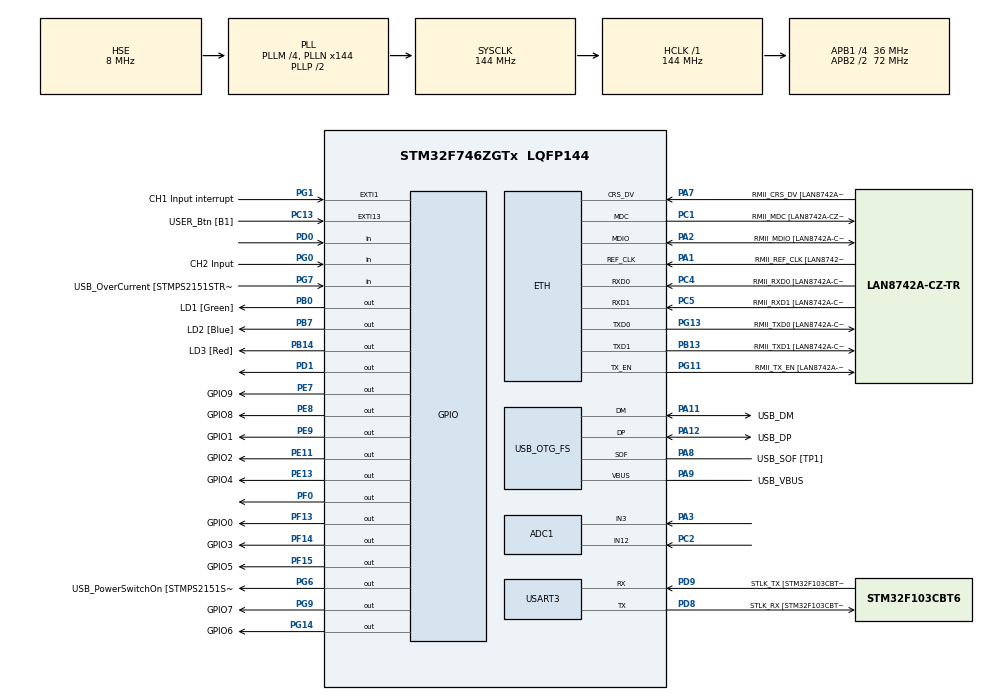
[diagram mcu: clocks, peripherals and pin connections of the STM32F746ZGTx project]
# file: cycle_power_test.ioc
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ADC1.Channel-0\#ChannelRegularConversion=ADC_CHANNEL_12
ADC1.NbrOfConversion=1
ADC1.NbrOfConversionFlag=1
ADC1.Rank-0\#ChannelRegularConversion=1
ADC1.SamplingTime-0\#ChannelRegularConversion=ADC_SAMPLETIME_3CYCLES
ADC1.master=1
ETH.MediaInterface=ETH_MEDIA_INTERFACE_RMII
ETH.PHY_Name=LAN8742A_PHY_ADDRESS
ETH.PHY_Value=0
ETH.PhyAddress=0
Mcu.Family=STM32F7
Mcu.Name=STM32F746ZGTx
Mcu.Package=LQFP144
NVIC.EXTI1_IRQn=true\:0\:0\:false\:false\:true\:true\:true\:true
NVIC.PriorityGroup=NVIC_PRIORITYGROUP_4
NVIC.TIM8_TRG_COM_TIM14_IRQn=true\:0\:0\:false\:false\:true\:true\:true\:true
PA1.GPIO_Label=RMII_REF_CLK [LAN8742A-CZ-TR_REFCLK0]
PA1.Mode=RMII
PA1.Signal=ETH_REF_CLK
PA10.GPIO_Label=USB_ID
PA10.Signal=USB_OTG_FS_ID
PA11.GPIO_Label=USB_DM
PA11.Mode=Device_Only
PA11.Signal=USB_OTG_FS_DM
PA12.GPIO_Label=USB_DP
PA12.Mode=Device_Only
PA12.Signal=USB_OTG_FS_DP
PA13.GPIO_Label=TMS
PA13.Mode=Serial_Wire
PA13.Signal=SYS_JTMS-SWDIO
PA14.GPIO_Label=TCK
PA14.Mode=Serial_Wire
PA14.Signal=SYS_JTCK-SWCLK
PA2.GPIO_Label=RMII_MDIO [LAN8742A-CZ-TR_MDIO]
PA2.Mode=RMII
PA2.Signal=ETH_MDIO
PA3.Signal=ADCx_IN3
PA7.GPIO_Label=RMII_CRS_DV [LAN8742A-CZ-TR_CRS_DV]
PA7.Mode=RMII
PA7.Signal=ETH_CRS_DV
PA8.GPIO_Label=USB_SOF [TP1]
PA8.Mode=Activate_SOF_FS
PA8.Signal=USB_OTG_FS_SOF
PA9.GPIO_Label=USB_VBUS
PA9.Mode=Activate_VBUS
PA9.Signal=USB_OTG_FS_VBUS
PB0.GPIO_Label=LD1 [Green]
PB0.PinState=GPIO_PIN_RESET
PB0.Signal=GPIO_Output
PB13.GPIO_Label=RMII_TXD1 [LAN8742A-CZ-TR_TXD1]
PB13.Mode=RMII
PB13.Signal=ETH_TXD1
PB14.GPIO_Label=LD3 [Red]
PB14.Signal=GPIO_Output
PB3.GPIO_Label=SW0
PB3.Signal=SYS_JTDO-SWO
PB7.GPIO_Label=LD2 [Blue]
PB7.Signal=GPIO_Output
PC1.GPIO_Label=RMII_MDC [LAN8742A-CZ-TR_MDC]
PC1.Mode=RMII
PC1.Signal=ETH_MDC
PC13.GPIO_Label=USER_Btn [B1]
PC13.Signal=GPXTI13
PC14/OSC32_IN.Mode=LSE-External-Oscillator
PC14/OSC32_IN.Signal=RCC_OSC32_IN
PC15/OSC32_OUT.Mode=LSE-External-Oscillator
PC15/OSC32_OUT.Signal=RCC_OSC32_OUT
PC2.Signal=ADCx_IN12
PC4.GPIO_Label=RMII_RXD0 [LAN8742A-CZ-TR_RXD0]
PC4.Mode=RMII
PC4.Signal=ETH_RXD0
PC5.GPIO_Label=RMII_RXD1 [LAN8742A-CZ-TR_RXD1]
PC5.Mode=RMII
PC5.Signal=ETH_RXD1
PD0.Signal=GPIO_Input
PD1.PinState=GPIO_PIN_RESET
PD1.Signal=GPIO_Output
PD8.GPIO_Label=STLK_RX [STM32F103CBT6_PA3]
PD8.Mode=Asynchronous
PD8.Signal=USART3_TX
PD9.GPIO_Label=STLK_TX [STM32F103CBT6_PA2]
PD9.Mode=Asynchronous
PD9.Signal=USART3_RX
PE11.GPIO_Label=GPIO2
PE11.PinState=GPIO_PIN_RESET
PE11.Signal=GPIO_Output
PE13.GPIO_Label=GPIO4
PE13.PinState=GPIO_PIN_RESET
PE13.Signal=GPIO_Output
PE7.GPIO_Label=GPIO9
PE7.PinState=GPIO_PIN_RESET
PE7.Signal=GPIO_Output
PE8.GPIO_Label=GPIO8
PE8.PinState=GPIO_PIN_RESET
PE8.Signal=GPIO_Output
PE9.GPIO_Label=GPIO1
PE9.PinState=GPIO_PIN_RESET
PE9.Signal=GPIO_Output
PF0.Signal=GPIO_Output
PF13.GPIO_Label=GPIO0
PF13.PinState=GPIO_PIN_RESET
PF13.Signal=GPIO_Output
PF14.GPIO_Label=GPIO3
PF14.PinState=GPIO_PIN_RESET
PF14.Signal=GPIO_Output
PF15.GPIO_Label=GPIO5
PF15.PinState=GPIO_PIN_RESET
PF15.Signal=GPIO_Output
PG0.GPIO_Label=CH2 Input
PG0.Signal=GPIO_Input
PG1.GPIO_Label=CH1 Input interrupt
PG1.GPIO_ModeDefaultEXTI=GPIO_MODE_IT_RISING_FALLING
PG1.Signal=GPXTI1
PG11.GPIO_Label=RMII_TX_EN [LAN8742A-CZ-TR_TXEN]
PG11.Mode=RMII
PG11.Signal=ETH_TX_EN
PG13.GPIO_Label=RMII_TXD0 [LAN8742A-CZ-TR_TXD0]
PG13.Mode=RMII
PG13.Signal=ETH_TXD0
PG14.GPIO_Label=GPIO6
PG14.PinState=GPIO_PIN_RESET
PG14.Signal=GPIO_Output
PG6.GPIO_Label=USB_PowerSwitchOn [STMPS2151STR_EN]
PG6.Signal=GPIO_Output
PG7.GPIO_Label=USB_OverCurrent [STMPS2151STR_FAULT]
PG7.Signal=GPIO_Input
PG9.GPIO_Label=GPIO7
PG9.PinState=GPIO_PIN_RESET
PG9.Signal=GPIO_Output
PH0/OSC_IN.GPIO_Label=MCO [STM32F103CBT6_PA8]
PH0/OSC_IN.Mode=HSE-External-Clock-Source
PH0/OSC_IN.Signal=RCC_OSC_IN
PH1/OSC_OUT.Mode=HSE-External-Clock-Source
PH1/OSC_OUT.Signal=RCC_OSC_OUT
ProjectManager.HeapSize=0x200
ProjectManager.StackSize=0x400
ProjectManager.TargetToolchain=STM32CubeIDE
RCC.48MHZClocksFreq_Value=24000000
RCC.AHBFreq_Value=144000000
RCC.APB1CLKDivider=RCC_HCLK_DIV4
RCC.APB1Freq_Value=36000000
RCC.APB1TimFreq_Value=72000000
RCC.APB2CLKDivider=RCC_HCLK_DIV2
RCC.APB2Freq_Value=72000000
RCC.APB2TimFreq_Value=144000000
RCC.CortexFreq_Value=144000000
RCC.HCLKFreq_Value=144000000
RCC.HSE_VALUE=8000000
RCC.HSI_VALUE=16000000
RCC.PLLM=4
RCC.PLLMUL=RCC_PLL_MUL9
RCC.PLLN=144
RCC.PLLQ=6
RCC.PRESCALERUSB=RCC_USBCLKSOURCE_PLL_DIV1_5
RCC.SYSCLKFreq_VALUE=144000000
RCC.SYSCLKSource=RCC_SYSCLKSOURCE_PLLCLK
RCC.SYSCLKSourceVirtual=RCC_SYSCLKSOURCE_PLLCLK
RCC.USBFreq_Value=48000000
RCC.VCOOutputFreq_Value=288000000
SH.ADCx_IN12.0=ADC1_IN12,IN12
SH.ADCx_IN3.0=ADC1_IN3,IN3
TIM14.Period=10000
TIM14.Prescaler=7200 -1 
USART3.VirtualMode-Asynchronous=VM_ASYNC
USB_OTG_FS.VirtualMode=Device_Only
VP_TIM14_VS_ClockSourceINT.Mode=Enable_Timer
board=NUCLEO-F746ZG

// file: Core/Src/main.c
/* USER CODE BEGIN Header */
/**
  ******************************************************************************
  * @file           : main.c
  * @brief          : Main program body
  ******************************************************************************
  * @attention
  *
  * Copyright (c) 2022 STMicroelectronics.
  * All rights reserved.
  *
  * This software is licensed under terms that can be found in the LICENSE file
  * in the root directory of this software component.
  * If no LICENSE file comes with this software, it is provided AS-IS.
  * Code written for AMTEC.PRO by Primož Peitl
  *
  ******************************************************************************
  */
/* USER CODE END Header */
#include "main.h"

/* USER CODE BEGIN Includes */
#include "string.h"
#include "stdio.h"
/* USER CODE END Includes */

/* USER CODE BEGIN PD */
#define DO_NOCURRENT_TEST 0
#define NO_CURRENT_ADC_VAL			1600
#define CURRENT_PRESENT_ADC_VAL		1700
#define ENABLE_IDLE_NTC_TOGGLE		0

//output pins
#define RUNNING				GPIO_PIN_0		//GPIOF
#define NTC_BANK			GPIO_PIN_8		//GPIOF
#define GEN_NO_ERROR		GPIO_PIN_7		//GPIOF
#define GEN_WARNING			GPIO_PIN_2		//GPIOD
#define CH2_TRIGGER			GPIO_PIN_9		//GPIOF
#define DEBUG_OFF_OUTPUT	0

//input pins

//Errors
#define LOW_CURRENT_ERROR	1

/* USER CODE END PD */

ADC_HandleTypeDef hadc1;

ETH_HandleTypeDef heth;

TIM_HandleTypeDef htim14;

UART_HandleTypeDef huart3;

PCD_HandleTypeDef hpcd_USB_OTG_FS;

/* USER CODE BEGIN PV */
volatile int activeCount 	= 0;

int i;
int cntDly 					= 0;
int my_HAL_Delay 			= 1;
float voltageSense;
int shuntValues[11];
int StartSet 				= 0;
int CurrADC_Val				= 0;
int cntNr [11];
int CycleNr 				= 0;
int NrOfADCs 				= 0;
int currVals[2000];
int curValsCntr 			= 0;
int currValsMax, currValsMin;
long  	IdleCounter 		= 0;
long  	OnStartDelay 		= 0;
volatile int 	CH2PulsCounter		= 0;
uint32_t CH1PulsCounter		= 0;
uint32_t CH1NegCounter		= 0;
volatile uint32_t intCH1PulsCounter	= 0;
volatile uint32_t intCH1NegCounter 	= 0;
volatile int32_t intDetected 		= 0;
volatile uint32_t startCNT;
uint32_t startNTCtoggle	= 0;
GPIO_PinState prev_CH1;
GPIO_PinState prev_CH2;
GPIO_PinState current_CH1;
GPIO_PinState current_CH2;
GPIO_PinState current_sense;
GPIO_PinState StartProcess;
GPIO_PinState GPTestEnabled;
GPIO_PinState RstBlockValues;

GPIO_PinState PLCClk;
GPIO_PinState PLCResData;
GPIO_PinState prev_PLCClock;
GPIO_PinState prev_PLCResData;
GPIO_PinState prev_StartProcess;

GPIO_PinState PLCClk_GP		= 0;
GPIO_PinState PLCResData_GP	= 0;
GPIO_PinState prev_PLCClock_GP;
GPIO_PinState prev_PLCResData_GP;

uint32_t ADC_currentPresent_val;
uint32_t ADC_noCurrent_val;

int PLCClockCounter_val;
uint16_t PLC_ClockIdleTicks = 0;
uint16_t ValuesPLCResData 	= 0x3ff;

int PLCClockCounterGP_val;
uint16_t GP_Cycles_tmp 		= 0;
uint16_t GP_Cycles			= 0;
uint32_t PLC_ClockIdleTicks_GP;

int FalseLowCurrentCounter;
int ErrorNr = 0;

unsigned int isPG0low 		= 0;
char myString[50];
char msg[255];
unsigned int FalsePG1;
unsigned int NrOfChanges_PG1;
unsigned char TestRunning;
unsigned int Counter1, Counter2,Counter3;

/* USER CODE END PV */

void SystemClock_Config(void);
static void MX_GPIO_Init(void);
static void MX_ETH_Init(void);
static void MX_USART3_UART_Init(void);
static void MX_USB_OTG_FS_PCD_Init(void);
static void MX_TIM14_Init(void);
static void MX_ADC1_Init(void);

/* USER CODE BEGIN PFP */
void ToggleNTCBank();
int CheckIdleCurrent();
void IdleCurrentMeasurementTest();
void DWT_Init(void);
/* USER CODE END PFP */

/* USER CODE BEGIN 0 */

// ----------------------------------------------------------------------------
// communication between PLC and MPU
// which parts are good and which are not
// ----------------------------------------------------------------------------
void BadPartDetect() {
uint16_t tmpVal;
	PLCClk		= HAL_GPIO_ReadPin(GPIOF, GPIO_PIN_1);			//PLC Clock
	PLCResData	= HAL_GPIO_ReadPin(GPIOE, GPIO_PIN_3);			//PLC resistor data

	if (PLCClockCounter_val > 9) PLCClockCounter_val = 0;

	//detect clock rise signal
	if (prev_PLCClock == GPIO_PIN_RESET && PLCClk == GPIO_PIN_SET)
	{
		if (PLCResData == GPIO_PIN_RESET) {
			tmpVal = (1 << PLCClockCounter_val);
			tmpVal = ~tmpVal;
			ValuesPLCResData &= tmpVal;
		}
		PLCClockCounter_val++;
	}

	// longer PLCClk reset means reset for PLCClockCounter_val
	if (PLCClk == GPIO_PIN_RESET) PLC_ClockIdleTicks++;
	else PLC_ClockIdleTicks = 0;

	if (PLC_ClockIdleTicks >= 10000) {
		/*
		if ((PLC_ClockIdleTicks == 10000) && (ValuesPLCResData != 0x3FF)) {
			sprintf(msg, "PLCClockCounter_val: %d, ValuesPLCResData:%d \r\n ",PLCClockCounter_val,ValuesPLCResData);
			HAL_UART_Transmit(&huart3, (uint8_t*)msg, strlen(msg), HAL_MAX_DELAY);
		}
		*/
		PLC_ClockIdleTicks = 10001;
		PLCClockCounter_val = 0;
	}

	prev_PLCClock = PLCClk;
	prev_PLCResData = PLCResData;
}

void GPTest_NrOfCycles() {
	PLCClk_GP		= HAL_GPIO_ReadPin(GPIOF, GPIO_PIN_1);				//PLC Clock
	PLCResData_GP	= HAL_GPIO_ReadPin(GPIOE, GPIO_PIN_3);				//PLC resistor data
	if (PLCClockCounterGP_val > 9) PLCClockCounterGP_val = 0;
	//detect clock rise signal
	if (prev_PLCClock_GP == GPIO_PIN_RESET && PLCClk_GP == GPIO_PIN_SET)
	{
		//GP_Cycles_tmp = GP_Cycles_tmp + 2^PLCClockCounterGP_val;
		if (PLCResData_GP == GPIO_PIN_SET) {
			GP_Cycles_tmp = GP_Cycles_tmp + (uint16_t)(1 << PLCClockCounterGP_val);
			//GP_Cycles_tmp += 1;
			//uint16_t GP_Cycles = 0;
		}
		PLCClockCounterGP_val++;
	}

	// longer PLCClk reset means reset for PLCClockCounter_val
	if (PLCClk_GP == GPIO_PIN_RESET) PLC_ClockIdleTicks_GP++;
	else PLC_ClockIdleTicks_GP = 0;

	if (PLC_ClockIdleTicks_GP >= 10000) {
		if (PLC_ClockIdleTicks_GP == 10000){
			GP_Cycles = GP_Cycles_tmp;
			GP_Cycles_tmp = 0;
			sprintf(msg, "GP_Cycles: %d\r\n ",GP_Cycles);
			HAL_UART_Transmit(&huart3, (uint8_t*)msg, strlen(msg), HAL_MAX_DELAY);
		}
		PLC_ClockIdleTicks_GP = 10001;
		PLCClockCounterGP_val = 0;
	}

	prev_PLCClock_GP = PLCClk_GP;
	prev_PLCResData_GP = PLCResData_GP;
}

// ----------------------------------------------------------------------------
// ADC read task
// ----------------------------------------------------------------------------
void ADCReadTask(){
	//start ADC conversion every 20 cycles
	if (cntDly % 20 == 0) {
		HAL_ADC_Start(&hadc1);

		HAL_StatusTypeDef myADC_Status 								= HAL_ADC_PollForConversion(&hadc1 , 100);
		if 		(myADC_Status == HAL_OK )			CurrADC_Val 	+= HAL_ADC_GetValue(&hadc1);
		else if (myADC_Status == HAL_TIMEOUT) 		CurrADC_Val 	= 9999;
		else 										CurrADC_Val 	= 9998;

		NrOfADCs++;
		shuntValues[activeCount] = CurrADC_Val / NrOfADCs;
		HAL_ADC_Stop(&hadc1);
	}
	cntNr[activeCount] = cntDly;
	cntDly++;
	return;
}

void ReadADC() {
	if (prev_CH1 == GPIO_PIN_RESET) {
		cntDly 			= 0;
		CurrADC_Val 	= 0;
		NrOfADCs 		= 0;
	}
	ADCReadTask();
	return;
}

void ReadADC_Low() {
	if (prev_CH1 == GPIO_PIN_SET) {
		cntDly 			= 0;
		CurrADC_Val 	= 0;
		NrOfADCs 		= 0;
	}
	ADCReadTask();
	return;
}

uint32_t ReadADC_cont() {
uint32_t myADC_val;

	//start ADC conversion
	HAL_ADC_Start(&hadc1);
	HAL_StatusTypeDef myADC_Status = HAL_ADC_PollForConversion(&hadc1 , 100);
	if 		(myADC_Status == HAL_OK )			myADC_val = HAL_ADC_GetValue(&hadc1);
	else if (myADC_Status == HAL_TIMEOUT) 		myADC_val = 9999;
	else 										myADC_val = 9998;

	myADC_val = HAL_ADC_GetValue(&hadc1);

	HAL_ADC_Stop(&hadc1);
	if (curValsCntr >= 0 && curValsCntr < 2000) {
		currVals[curValsCntr] = myADC_val;
		curValsCntr++;
	}
	return myADC_val;
}

/* USER CODE END 0 */

int main(void)
{

	/* MCU Configuration--------------------------------------------------------*/

	/* Reset of all peripherals, Initialises the Flash interface and the Systick. */
	HAL_Init();

	/* Configure the system clock */
	SystemClock_Config();

	/* Initialise all configured peripherals */
	MX_GPIO_Init();
	if (0) MX_ETH_Init();				// disabled
	MX_USART3_UART_Init();
	if (0) MX_USB_OTG_FS_PCD_Init();  // disabled
	if (0) MX_TIM14_Init();			// disabled
	MX_ADC1_Init();

	/* USER CODE BEGIN 2 */
	DWT_Init();
	/* USER CODE END 2 */

	/* USER CODE BEGIN WHILE */
	HAL_GPIO_WritePin(GPIOB, LD2_Pin, GPIO_PIN_RESET);
	sprintf(msg, "BOOTING \r\n");
	HAL_UART_Transmit(&huart3, (uint8_t*)msg, strlen(msg), HAL_MAX_DELAY);

	ADC_currentPresent_val 	= CURRENT_PRESENT_ADC_VAL;		// store constant values to variables
	ADC_noCurrent_val 		= NO_CURRENT_ADC_VAL;
	StartSet = 1;												// low start state must be detected before
															// before doing first start
	HAL_GPIO_WritePin(GPIOF, CH2_TRIGGER, GPIO_PIN_RESET);	// reset trigger for CH2

  /* USER CODE END WHILE */

  /* USER CODE BEGIN 3 */
	HAL_GPIO_WritePin(GPIOF, GPIO_PIN_13, 	GPIO_PIN_RESET);
	HAL_GPIO_WritePin(GPIOE, GPIO_PIN_9, 	GPIO_PIN_RESET);
	HAL_GPIO_WritePin(GPIOE, GPIO_PIN_11, 	GPIO_PIN_RESET);
	HAL_GPIO_WritePin(GPIOF, GPIO_PIN_14, 	GPIO_PIN_RESET);
	HAL_GPIO_WritePin(GPIOE, GPIO_PIN_13, 	GPIO_PIN_RESET);
	HAL_GPIO_WritePin(GPIOF, GPIO_PIN_15, 	GPIO_PIN_RESET);
	HAL_GPIO_WritePin(GPIOG, GPIO_PIN_14, 	GPIO_PIN_RESET);
	HAL_GPIO_WritePin(GPIOG, GPIO_PIN_9, 	GPIO_PIN_RESET);
	HAL_GPIO_WritePin(GPIOE, GPIO_PIN_8, 	GPIO_PIN_RESET);
	HAL_GPIO_WritePin(GPIOE, GPIO_PIN_7, 	GPIO_PIN_RESET);
	activeCount = 0;		//select first IGBT. It will switch on after start signal
/* Infinite loop */
	startNTCtoggle	= HAL_GetTick();
	while (1) {
//detect input signals
		current_CH1 	= HAL_GPIO_ReadPin(GPIOG, GPIO_PIN_1);			//CH1 from generator
		current_CH2 	= HAL_GPIO_ReadPin(GPIOG, GPIO_PIN_0);			//CH2 from generator
		StartProcess 	= HAL_GPIO_ReadPin(GPIOF, GPIO_PIN_2);			//Start pulse from PLC
		GPTestEnabled	= HAL_GPIO_ReadPin(GPIOE, GPIO_PIN_6);			//GP signal from PLC
		RstBlockValues	= HAL_GPIO_ReadPin(GPIOE, GPIO_PIN_1);			//Start pulse from PLC

//detect start pulse from PLC
		if (OnStartDelay++ > 20000) OnStartDelay = 20000;
		if (StartProcess == GPIO_PIN_SET && StartSet == 0 && OnStartDelay > 10000)
		{
			HAL_GPIO_WritePin(GPIOF, CH2_TRIGGER, GPIO_PIN_SET);	//trigger ch2
			StartSet 		= 1;
			ErrorNr 		= 0;											//reset errors when start pulse
			Counter1++;
		}
		else if (StartProcess == GPIO_PIN_RESET && StartSet == 1)
		{
			HAL_GPIO_WritePin(GPIOF, CH2_TRIGGER, GPIO_PIN_RESET);	//reset trigger for CH2
			StartSet = 0;
			Counter2++;
		}
// this happens only at the start of the cycle
// if cyclecount > 1 this doesn't occurs
		if  (StartProcess == GPIO_PIN_RESET && GPTestEnabled == GPIO_PIN_SET)
		{
			ValuesPLCResData 	= 0x3ff;
			intCH1PulsCounter 	= 0;
			intCH1NegCounter 	= 0;
			CH2PulsCounter 		= 0;
			HAL_GPIO_WritePin(GPIOF, NTC_BANK, GPIO_PIN_RESET);		//reset temperature bank select pin
			startNTCtoggle	= HAL_GetTick();
		}
//switch on warrning light
		if (prev_CH2 == GPIO_PIN_RESET && current_CH2 == GPIO_PIN_SET) {
			HAL_GPIO_WritePin(GPIOD, GEN_WARNING, GPIO_PIN_SET);
		}
//RstBlockValues reset command
		if (RstBlockValues)
		{
			sprintf(msg, "RstBlockValues ON\r\n");
			HAL_UART_Transmit(&huart3, (uint8_t*)msg, strlen(msg), HAL_MAX_DELAY);
			ValuesPLCResData 	= 0x3ff;
			intCH1PulsCounter 	= 0;
			CH2PulsCounter 		= 0;
		}
		if (Counter1 > 65000) Counter1=0;
		if (Counter2 > 65000) Counter2=0;

//detect not allowed input signals
		if (current_CH1 == GPIO_PIN_SET && (current_CH2 == GPIO_PIN_RESET || StartProcess == GPIO_PIN_RESET)) FalsePG1++;
		if (prev_CH1 != current_CH1) NrOfChanges_PG1++;

// toggle NTC bank
		if ((HAL_GetTick() - startNTCtoggle >= 500) && (StartProcess == GPIO_PIN_SET))
		{
			startNTCtoggle += 500;
			HAL_GPIO_TogglePin(GPIOF, NTC_BANK);
			//sprintf(msg, "0x%X \r\n",ValuesPLCResData);
			//HAL_UART_Transmit(&huart3, (uint8_t*)msg, strlen(msg), HAL_MAX_DELAY);
		}

		if(current_CH2 == GPIO_PIN_SET && StartProcess == GPIO_PIN_SET && ErrorNr == 0 && OnStartDelay > 10000) {
			//this is done in interrupt
		}
		else {
	// switch off outputs
	// interrupt hasen't occurred for a intDetected cycles
			intDetected--;
			int32_t t_initDetect = intDetected;
			if (t_initDetect == 0) {
				__disable_irq();
				HAL_GPIO_WritePin(GPIOF, GPIO_PIN_13, 	GPIO_PIN_RESET);
				HAL_GPIO_WritePin(GPIOE, GPIO_PIN_9, 	GPIO_PIN_RESET);
				HAL_GPIO_WritePin(GPIOE, GPIO_PIN_11, 	GPIO_PIN_RESET);
				HAL_GPIO_WritePin(GPIOF, GPIO_PIN_14, 	GPIO_PIN_RESET);
				HAL_GPIO_WritePin(GPIOE, GPIO_PIN_13, 	GPIO_PIN_RESET);
				HAL_GPIO_WritePin(GPIOF, GPIO_PIN_15, 	GPIO_PIN_RESET);
				HAL_GPIO_WritePin(GPIOG, GPIO_PIN_14, 	GPIO_PIN_RESET);
				HAL_GPIO_WritePin(GPIOG, GPIO_PIN_9, 	GPIO_PIN_RESET);
				HAL_GPIO_WritePin(GPIOE, GPIO_PIN_8, 	GPIO_PIN_RESET);
				HAL_GPIO_WritePin(GPIOE, GPIO_PIN_7, 	GPIO_PIN_RESET);
				activeCount = 0; 											//select first IGBT. It will switch on after start signal
				__enable_irq();
				uint32_t end = DWT->CYCCNT;
				uint32_t cycles = end - startCNT;
				uint32_t us = cycles / (SystemCoreClock / 1000000U);
				sprintf(msg, "Reset IGBTs: %1u\r\n", (uint16_t)us);
				HAL_UART_Transmit(&huart3, (uint8_t*)msg, strlen(msg), HAL_MAX_DELAY);
			}
			else if (t_initDetect < 0) {
				intDetected = -1;
			//reset output RUNNING
				IdleCounter++;

				if (IdleCounter == 42000) {
					uint32_t end = DWT->CYCCNT;
					uint32_t cycles = end - startCNT;
					uint32_t us = cycles / (SystemCoreClock / 1000000U);
					HAL_GPIO_WritePin(GPIOF, RUNNING,	GPIO_PIN_RESET);
					sprintf(msg, "Reset RUNNING: %1u\r\n", us);
					HAL_UART_Transmit(&huart3, (uint8_t*)msg, strlen(msg), HAL_MAX_DELAY);
				}
				if (IdleCounter > 100000) IdleCounter = 100000;

		//toggle NTC bank in idle state - if enabled
				if (ENABLE_IDLE_NTC_TOGGLE) ToggleNTCBank();

				//write low level values - test
				if (DO_NOCURRENT_TEST) IdleCurrentMeasurementTest();
			}
		}
	 // call bad part detection procedure
		if (!GPTestEnabled)
		{
			BadPartDetect();
		}
		// check for GP test nr of cycles
		if (StartProcess == GPIO_PIN_RESET && GPTestEnabled ) {
			GPTest_NrOfCycles();
		}

		if (StartProcess == GPIO_PIN_RESET && StartProcess !=prev_StartProcess) {
			sprintf(msg, "Measurement finished: %u, %u, 0x%x\r\n", CH1PulsCounter, CH1NegCounter, ValuesPLCResData);
			HAL_UART_Transmit(&huart3, (uint8_t*)msg, strlen(msg), HAL_MAX_DELAY);
		}

		// remember state of inputs
		 prev_CH1 = current_CH1;
		 prev_CH2 = current_CH2;
		 prev_StartProcess = StartProcess;
		 CH1PulsCounter = intCH1PulsCounter;
		 CH1NegCounter 	= intCH1NegCounter;
	}
  /* USER CODE END 3 */
}

void HAL_GPIO_EXTI_Callback( uint16_t GPIO_Pin)	//Interrupt for GPIO pins
{
	char tmpResult;
	GPIO_PinState	EXTI_current_CH1 	= HAL_GPIO_ReadPin(GPIOG, GPIO_PIN_1);			//CH1 from generator
	GPIO_PinState 	EXTI_current_CH2 	= HAL_GPIO_ReadPin(GPIOG, GPIO_PIN_0);			//CH2 from generator
	GPIO_PinState 	EXTI_StartProcess 	= HAL_GPIO_ReadPin(GPIOF, GPIO_PIN_2);			//Start pulse from PLC

	//if (EXTI_current_CH1 == GPIO_PIN_SET) intCH1PulsCounter++;
	intDetected = 40000;
	startCNT = DWT->CYCCNT;

//	if(GPIO_Pin == GPIO_PIN_1 && EXTI_current_CH1 == GPIO_PIN_SET && EXTI_current_CH2 == GPIO_PIN_SET && EXTI_StartProcess == GPIO_PIN_SET && ErrorNr == 0 && OnStartDelay > 10000) {
	if(GPIO_Pin == GPIO_PIN_1 && EXTI_current_CH1 == GPIO_PIN_SET && EXTI_StartProcess == GPIO_PIN_SET && ErrorNr == 0 && OnStartDelay > 10000) {
		 HAL_GPIO_WritePin(GPIOF, RUNNING,	GPIO_PIN_SET);
		 IdleCounter = 0;
		 curValsCntr = 0;
		 intCH1PulsCounter++;
	 //***************************************************
	 //************* Forcing all IGBTs to work
	 //***************************************************
		 if (intCH1PulsCounter == 1) ValuesPLCResData = 0x3ff;
	 //***************************************************
	 //***************************************************
	 //***************************************************
		 switch (activeCount) {
			case 0:
			//	HAL_GPIO_WritePin(GPIOF, GPIO_PIN_13,	GPIO_PIN_SET && (CH2PulsCounter != 50) && !(GPTestEnabled && CH2PulsCounter > 50) && (ValuesPLCResData & (1 << activeCount)));
				tmpResult = !(GPTestEnabled && CH2PulsCounter > 50) && (ValuesPLCResData & (1 << activeCount));
				HAL_GPIO_WritePin(GPIOF, GPIO_PIN_13,	GPIO_PIN_SET && tmpResult);
				HAL_GPIO_WritePin(GPIOE, GPIO_PIN_9, 	GPIO_PIN_RESET);
				HAL_GPIO_WritePin(GPIOE, GPIO_PIN_11, 	GPIO_PIN_RESET);
				HAL_GPIO_WritePin(GPIOF, GPIO_PIN_14, 	GPIO_PIN_RESET);
				HAL_GPIO_WritePin(GPIOE, GPIO_PIN_13, 	GPIO_PIN_RESET);
				HAL_GPIO_WritePin(GPIOF, GPIO_PIN_15, 	GPIO_PIN_RESET);
				HAL_GPIO_WritePin(GPIOG, GPIO_PIN_14, 	GPIO_PIN_RESET);
				HAL_GPIO_WritePin(GPIOG, GPIO_PIN_9, 	GPIO_PIN_RESET);
				HAL_GPIO_WritePin(GPIOE, GPIO_PIN_8, 	GPIO_PIN_RESET);
				HAL_GPIO_WritePin(GPIOE, GPIO_PIN_7, 	GPIO_PIN_RESET);
#ifdef DEBUGINT
				sprintf(msg, "%u, %u \r\n",  activeCount, tmpResult);
				HAL_UART_Transmit(&huart3, (uint8_t*)msg, strlen(msg), HAL_MAX_DELAY);
#endif
				//sprintf(msg, "%03d, %d \r\n", EXTI_current_CH1 * 100 + EXTI_current_CH2 * 10 + EXTI_StartProcess, intCH1PulsCounter);
				//sprintf(msg, "%03u \r\n",  intCH1PulsCounter);
				//HAL_UART_Transmit(&huart3, (uint8_t*)msg, strlen(msg), HAL_MAX_DELAY);

				break;
			case 1:
				tmpResult = !(GPTestEnabled && CH2PulsCounter > 70) && (ValuesPLCResData & (1 << activeCount));
				HAL_GPIO_WritePin(GPIOF, GPIO_PIN_13, 	GPIO_PIN_RESET);
				HAL_GPIO_WritePin(GPIOE, GPIO_PIN_9, 	GPIO_PIN_SET && tmpResult);
				HAL_GPIO_WritePin(GPIOE, GPIO_PIN_11, 	GPIO_PIN_RESET);
				HAL_GPIO_WritePin(GPIOF, GPIO_PIN_14, 	GPIO_PIN_RESET);
				HAL_GPIO_WritePin(GPIOE, GPIO_PIN_13, 	GPIO_PIN_RESET);
				HAL_GPIO_WritePin(GPIOF, GPIO_PIN_15, 	GPIO_PIN_RESET);
				HAL_GPIO_WritePin(GPIOG, GPIO_PIN_14, 	GPIO_PIN_RESET);
				HAL_GPIO_WritePin(GPIOG, GPIO_PIN_9, 	GPIO_PIN_RESET);
				HAL_GPIO_WritePin(GPIOE, GPIO_PIN_8, 	GPIO_PIN_RESET);
				HAL_GPIO_WritePin(GPIOE, GPIO_PIN_7, 	GPIO_PIN_RESET);
#ifdef DEBUGINT
				sprintf(msg, "%u, %u \r\n",  activeCount, tmpResult);
				HAL_UART_Transmit(&huart3, (uint8_t*)msg, strlen(msg), HAL_MAX_DELAY);
#endif
				break;
			case 2:
				tmpResult = !(GPTestEnabled && CH2PulsCounter > 90) && (ValuesPLCResData & (1 << activeCount));
				HAL_GPIO_WritePin(GPIOF, GPIO_PIN_13, 	GPIO_PIN_RESET);
				HAL_GPIO_WritePin(GPIOE, GPIO_PIN_9, 	GPIO_PIN_RESET);
				HAL_GPIO_WritePin(GPIOE, GPIO_PIN_11, 	GPIO_PIN_SET && tmpResult );
				HAL_GPIO_WritePin(GPIOF, GPIO_PIN_14, 	GPIO_PIN_RESET);
				HAL_GPIO_WritePin(GPIOE, GPIO_PIN_13, 	GPIO_PIN_RESET);
				HAL_GPIO_WritePin(GPIOF, GPIO_PIN_15, 	GPIO_PIN_RESET);
				HAL_GPIO_WritePin(GPIOG, GPIO_PIN_14, 	GPIO_PIN_RESET);
				HAL_GPIO_WritePin(GPIOG, GPIO_PIN_9, 	GPIO_PIN_RESET);
				HAL_GPIO_WritePin(GPIOE, GPIO_PIN_8, 	GPIO_PIN_RESET);
				HAL_GPIO_WritePin(GPIOE, GPIO_PIN_7, 	GPIO_PIN_RESET);
#ifdef DEBUGINT
				sprintf(msg, "%u, %u \r\n",  activeCount, tmpResult);
				HAL_UART_Transmit(&huart3, (uint8_t*)msg, strlen(msg), HAL_MAX_DELAY);
#endif
				break;
			case 3:
				tmpResult = !(GPTestEnabled && CH2PulsCounter > 110) && (ValuesPLCResData & (1 << activeCount));
				HAL_GPIO_WritePin(GPIOF, GPIO_PIN_13, 	GPIO_PIN_RESET);
				HAL_GPIO_WritePin(GPIOE, GPIO_PIN_9, 	GPIO_PIN_RESET);
				HAL_GPIO_WritePin(GPIOE, GPIO_PIN_11, 	GPIO_PIN_RESET);
				HAL_GPIO_WritePin(GPIOF, GPIO_PIN_14, 	GPIO_PIN_SET && tmpResult);
				HAL_GPIO_WritePin(GPIOE, GPIO_PIN_13, 	GPIO_PIN_RESET);
				HAL_GPIO_WritePin(GPIOF, GPIO_PIN_15, 	GPIO_PIN_RESET);
				HAL_GPIO_WritePin(GPIOG, GPIO_PIN_14, 	GPIO_PIN_RESET);
				HAL_GPIO_WritePin(GPIOG, GPIO_PIN_9, 	GPIO_PIN_RESET);
				HAL_GPIO_WritePin(GPIOE, GPIO_PIN_8, 	GPIO_PIN_RESET);
				HAL_GPIO_WritePin(GPIOE, GPIO_PIN_7, 	GPIO_PIN_RESET);
#ifdef DEBUGINT
				sprintf(msg, "%u, %u \r\n",  activeCount, tmpResult);
				HAL_UART_Transmit(&huart3, (uint8_t*)msg, strlen(msg), HAL_MAX_DELAY);
#endif
				break;
			case 4:
				tmpResult = !(GPTestEnabled && CH2PulsCounter > 130) && (ValuesPLCResData & (1 << activeCount));
				HAL_GPIO_WritePin(GPIOF, GPIO_PIN_13, 	GPIO_PIN_RESET);
				HAL_GPIO_WritePin(GPIOE, GPIO_PIN_9, 	GPIO_PIN_RESET);
				HAL_GPIO_WritePin(GPIOE, GPIO_PIN_11, 	GPIO_PIN_RESET);
				HAL_GPIO_WritePin(GPIOF, GPIO_PIN_14, 	GPIO_PIN_RESET);
				HAL_GPIO_WritePin(GPIOE, GPIO_PIN_13, 	GPIO_PIN_SET && tmpResult);
				HAL_GPIO_WritePin(GPIOF, GPIO_PIN_15, 	GPIO_PIN_RESET);
				HAL_GPIO_WritePin(GPIOG, GPIO_PIN_14, 	GPIO_PIN_RESET);
				HAL_GPIO_WritePin(GPIOG, GPIO_PIN_9, 	GPIO_PIN_RESET);
				HAL_GPIO_WritePin(GPIOE, GPIO_PIN_8, 	GPIO_PIN_RESET);
				HAL_GPIO_WritePin(GPIOE, GPIO_PIN_7, 	GPIO_PIN_RESET);
#ifdef DEBUGINT
				sprintf(msg, "%u, %u \r\n",  activeCount, tmpResult);
				HAL_UART_Transmit(&huart3, (uint8_t*)msg, strlen(msg), HAL_MAX_DELAY);
#endif
				break;
			case 5:
				tmpResult = !(GPTestEnabled && CH2PulsCounter > 150) && (ValuesPLCResData & (1 << activeCount));
				HAL_GPIO_WritePin(GPIOF, GPIO_PIN_13, 	GPIO_PIN_RESET);
				HAL_GPIO_WritePin(GPIOE, GPIO_PIN_9, 	GPIO_PIN_RESET);
				HAL_GPIO_WritePin(GPIOE, GPIO_PIN_11, 	GPIO_PIN_RESET);
				HAL_GPIO_WritePin(GPIOF, GPIO_PIN_14, 	GPIO_PIN_RESET);
				HAL_GPIO_WritePin(GPIOE, GPIO_PIN_13, 	GPIO_PIN_RESET);
				HAL_GPIO_WritePin(GPIOF, GPIO_PIN_15, 	GPIO_PIN_SET && tmpResult);
				HAL_GPIO_WritePin(GPIOG, GPIO_PIN_14, 	GPIO_PIN_RESET);
				HAL_GPIO_WritePin(GPIOG, GPIO_PIN_9, 	GPIO_PIN_RESET);
				HAL_GPIO_WritePin(GPIOE, GPIO_PIN_8, 	GPIO_PIN_RESET);
				HAL_GPIO_WritePin(GPIOE, GPIO_PIN_7, 	GPIO_PIN_RESET);
#ifdef DEBUGINT
				sprintf(msg, "%u, %u \r\n",  activeCount, tmpResult);
				HAL_UART_Transmit(&huart3, (uint8_t*)msg, strlen(msg), HAL_MAX_DELAY);
#endif
				break;
			case 6:
				tmpResult = !(GPTestEnabled && CH2PulsCounter > 170) && (ValuesPLCResData & (1 << activeCount));
				HAL_GPIO_WritePin(GPIOF, GPIO_PIN_13, 	GPIO_PIN_RESET);
				HAL_GPIO_WritePin(GPIOE, GPIO_PIN_9, 	GPIO_PIN_RESET);
				HAL_GPIO_WritePin(GPIOE, GPIO_PIN_11, 	GPIO_PIN_RESET);
				HAL_GPIO_WritePin(GPIOF, GPIO_PIN_14, 	GPIO_PIN_RESET);
				HAL_GPIO_WritePin(GPIOE, GPIO_PIN_13, 	GPIO_PIN_RESET);
				HAL_GPIO_WritePin(GPIOF, GPIO_PIN_15, 	GPIO_PIN_RESET);
				HAL_GPIO_WritePin(GPIOG, GPIO_PIN_14, 	GPIO_PIN_SET && tmpResult);
				HAL_GPIO_WritePin(GPIOG, GPIO_PIN_9, 	GPIO_PIN_RESET);
				HAL_GPIO_WritePin(GPIOE, GPIO_PIN_8, 	GPIO_PIN_RESET);
				HAL_GPIO_WritePin(GPIOE, GPIO_PIN_7, 	GPIO_PIN_RESET);
				break;
			case 7:
				HAL_GPIO_WritePin(GPIOF, GPIO_PIN_13, 	GPIO_PIN_RESET);
				HAL_GPIO_WritePin(GPIOE, GPIO_PIN_9, 	GPIO_PIN_RESET);
				HAL_GPIO_WritePin(GPIOE, GPIO_PIN_11, 	GPIO_PIN_RESET);
				HAL_GPIO_WritePin(GPIOF, GPIO_PIN_14, 	GPIO_PIN_RESET);
				HAL_GPIO_WritePin(GPIOE, GPIO_PIN_13, 	GPIO_PIN_RESET);
				HAL_GPIO_WritePin(GPIOF, GPIO_PIN_15, 	GPIO_PIN_RESET);
				HAL_GPIO_WritePin(GPIOG, GPIO_PIN_14, 	GPIO_PIN_RESET);
				HAL_GPIO_WritePin(GPIOG, GPIO_PIN_9, 	GPIO_PIN_SET && !(GPTestEnabled && CH2PulsCounter > 190) && (ValuesPLCResData & (1 << activeCount)));
				HAL_GPIO_WritePin(GPIOE, GPIO_PIN_8, 	GPIO_PIN_RESET);
				HAL_GPIO_WritePin(GPIOE, GPIO_PIN_7, 	GPIO_PIN_RESET);
				break;
			case 8:
				HAL_GPIO_WritePin(GPIOF, GPIO_PIN_13, 	GPIO_PIN_RESET);
				HAL_GPIO_WritePin(GPIOE, GPIO_PIN_9, 	GPIO_PIN_RESET);
				HAL_GPIO_WritePin(GPIOE, GPIO_PIN_11, 	GPIO_PIN_RESET);
				HAL_GPIO_WritePin(GPIOF, GPIO_PIN_14, 	GPIO_PIN_RESET);
				HAL_GPIO_WritePin(GPIOE, GPIO_PIN_13, 	GPIO_PIN_RESET);
				HAL_GPIO_WritePin(GPIOF, GPIO_PIN_15, 	GPIO_PIN_RESET);
				HAL_GPIO_WritePin(GPIOG, GPIO_PIN_14, 	GPIO_PIN_RESET);
				HAL_GPIO_WritePin(GPIOG, GPIO_PIN_9, 	GPIO_PIN_RESET);
				HAL_GPIO_WritePin(GPIOE, GPIO_PIN_8, 	GPIO_PIN_SET && !(GPTestEnabled && CH2PulsCounter > 210) && (ValuesPLCResData & (1 << activeCount)));
				HAL_GPIO_WritePin(GPIOE, GPIO_PIN_7, 	GPIO_PIN_RESET);
				break;
			case 9:
				HAL_GPIO_WritePin(GPIOF, GPIO_PIN_13, 	GPIO_PIN_RESET);
				HAL_GPIO_WritePin(GPIOE, GPIO_PIN_9, 	GPIO_PIN_RESET);
				HAL_GPIO_WritePin(GPIOE, GPIO_PIN_11, 	GPIO_PIN_RESET);
				HAL_GPIO_WritePin(GPIOF, GPIO_PIN_14, 	GPIO_PIN_RESET);
				HAL_GPIO_WritePin(GPIOE, GPIO_PIN_13, 	GPIO_PIN_RESET);
				HAL_GPIO_WritePin(GPIOF, GPIO_PIN_15, 	GPIO_PIN_RESET);
				HAL_GPIO_WritePin(GPIOG, GPIO_PIN_14, 	GPIO_PIN_RESET);
				HAL_GPIO_WritePin(GPIOG, GPIO_PIN_9, 	GPIO_PIN_RESET);
				HAL_GPIO_WritePin(GPIOE, GPIO_PIN_8, 	GPIO_PIN_RESET);
				HAL_GPIO_WritePin(GPIOE, GPIO_PIN_7, 	GPIO_PIN_SET && !(GPTestEnabled && CH2PulsCounter > 230) && (ValuesPLCResData & (1 << activeCount)));
				break;
			default:
				HAL_GPIO_WritePin(GPIOF, GPIO_PIN_13, 	GPIO_PIN_RESET); 	//
				HAL_GPIO_WritePin(GPIOE, GPIO_PIN_9, 	GPIO_PIN_RESET);  	//
				HAL_GPIO_WritePin(GPIOE, GPIO_PIN_11, 	GPIO_PIN_RESET); 	//
				HAL_GPIO_WritePin(GPIOF, GPIO_PIN_14, 	GPIO_PIN_RESET); 	//
				HAL_GPIO_WritePin(GPIOE, GPIO_PIN_13, 	GPIO_PIN_RESET);  	//
				HAL_GPIO_WritePin(GPIOF, GPIO_PIN_15, 	GPIO_PIN_RESET);  	//
				HAL_GPIO_WritePin(GPIOG, GPIO_PIN_14, 	GPIO_PIN_RESET);  	//
				HAL_GPIO_WritePin(GPIOG, GPIO_PIN_9, 	GPIO_PIN_RESET);  	//
				HAL_GPIO_WritePin(GPIOE, GPIO_PIN_8, 	GPIO_PIN_RESET);  	//
				HAL_GPIO_WritePin(GPIOE, GPIO_PIN_7, 	GPIO_PIN_RESET);  	//
				break;
		 }
	}
	if (GPIO_Pin == GPIO_PIN_1 && EXTI_current_CH1 == GPIO_PIN_RESET)
	{
		activeCount++;
		intCH1NegCounter++;
		cntDly = 0;
		if (activeCount >= 10) {
			activeCount = 0;
			CH2PulsCounter++;
		}

		 //CH1 = low, CH2 = high, Start = HIGH
		 HAL_GPIO_WritePin(GPIOF, GPIO_PIN_13, 	GPIO_PIN_RESET); //
		 HAL_GPIO_WritePin(GPIOE, GPIO_PIN_9, 	GPIO_PIN_RESET);  //
		 HAL_GPIO_WritePin(GPIOE, GPIO_PIN_11, 	GPIO_PIN_RESET); //
		 HAL_GPIO_WritePin(GPIOF, GPIO_PIN_14, 	GPIO_PIN_RESET); //
		 HAL_GPIO_WritePin(GPIOE, GPIO_PIN_13, 	GPIO_PIN_RESET);  //
		 HAL_GPIO_WritePin(GPIOF, GPIO_PIN_15, 	GPIO_PIN_RESET);  //
		 HAL_GPIO_WritePin(GPIOG, GPIO_PIN_14, 	GPIO_PIN_RESET);  //
		 HAL_GPIO_WritePin(GPIOG, GPIO_PIN_9, 	GPIO_PIN_RESET);  //
		 HAL_GPIO_WritePin(GPIOE, GPIO_PIN_8, 	GPIO_PIN_RESET);  //
		 HAL_GPIO_WritePin(GPIOE, GPIO_PIN_7, 	GPIO_PIN_RESET);  //

	}
}

void SystemClock_Config(void)
{
  RCC_OscInitTypeDef RCC_OscInitStruct = {0};
  RCC_ClkInitTypeDef RCC_ClkInitStruct = {0};

  /** Configure LSE Drive Capability
  */
  HAL_PWR_EnableBkUpAccess();

  /** Configure the main internal regulator output voltage
  */
  __HAL_RCC_PWR_CLK_ENABLE();
  __HAL_PWR_VOLTAGESCALING_CONFIG(PWR_REGULATOR_VOLTAGE_SCALE3);

  /** Initializes the RCC Oscillators according to the specified parameters
  * in the RCC_OscInitTypeDef structure.
  */
  RCC_OscInitStruct.OscillatorType 	= RCC_OSCILLATORTYPE_HSE;
  RCC_OscInitStruct.HSEState 		= RCC_HSE_BYPASS;
  RCC_OscInitStruct.PLL.PLLState 	= RCC_PLL_ON;
  RCC_OscInitStruct.PLL.PLLSource 	= RCC_PLLSOURCE_HSE;
  RCC_OscInitStruct.PLL.PLLM 		= 4;
  RCC_OscInitStruct.PLL.PLLN 		= 144;
  RCC_OscInitStruct.PLL.PLLP 		= RCC_PLLP_DIV2;
  RCC_OscInitStruct.PLL.PLLQ 		= 6;
  if (HAL_RCC_OscConfig(&RCC_OscInitStruct) != HAL_OK)
  {
    Error_Handler();
  }

  /** Initializes the CPU, AHB and APB buses clocks
  */
  RCC_ClkInitStruct.ClockType = RCC_CLOCKTYPE_HCLK|RCC_CLOCKTYPE_SYSCLK
                              |RCC_CLOCKTYPE_PCLK1|RCC_CLOCKTYPE_PCLK2;
  RCC_ClkInitStruct.SYSCLKSource = RCC_SYSCLKSOURCE_PLLCLK;
  RCC_ClkInitStruct.AHBCLKDivider = RCC_SYSCLK_DIV1;
  RCC_ClkInitStruct.APB1CLKDivider = RCC_HCLK_DIV4;
  RCC_ClkInitStruct.APB2CLKDivider = RCC_HCLK_DIV2;

  if (HAL_RCC_ClockConfig(&RCC_ClkInitStruct, FLASH_LATENCY_4) != HAL_OK)
  {
    Error_Handler();
  }
}

static void MX_ADC1_Init(void)
{

  ADC_ChannelConfTypeDef sConfig = {0};

  /** Configure the global features of the ADC (Clock, Resolution, Data Alignment and number of conversion)
  */
  hadc1.Instance 					= ADC1;
  hadc1.Init.ClockPrescaler 		= ADC_CLOCK_SYNC_PCLK_DIV2;
  hadc1.Init.Resolution 			= ADC_RESOLUTION_12B;
  hadc1.Init.ScanConvMode 			= ADC_SCAN_DISABLE;
  hadc1.Init.ContinuousConvMode 	= DISABLE;
  hadc1.Init.DiscontinuousConvMode 	= DISABLE;
  hadc1.Init.ExternalTrigConvEdge 	= ADC_EXTERNALTRIGCONVEDGE_NONE;
  hadc1.Init.ExternalTrigConv 		= ADC_SOFTWARE_START;
  hadc1.Init.DataAlign 				= ADC_DATAALIGN_RIGHT;
  hadc1.Init.NbrOfConversion 		= 1;
  hadc1.Init.DMAContinuousRequests 	= DISABLE;
  hadc1.Init.EOCSelection 			= ADC_EOC_SINGLE_CONV;
  if (HAL_ADC_Init(&hadc1) != HAL_OK)
  {
    Error_Handler();
  }

  /** Configure for the selected ADC regular channel its corresponding rank in the sequencer and its sample time.
  */
  sConfig.Channel = ADC_CHANNEL_12;
  sConfig.Rank = ADC_REGULAR_RANK_1;
  sConfig.SamplingTime = ADC_SAMPLETIME_3CYCLES;
  if (HAL_ADC_ConfigChannel(&hadc1, &sConfig) != HAL_OK)
  {
    Error_Handler();
  }

}

static void MX_ETH_Init(void)
{

   static uint8_t MACAddr[6];

  heth.Instance 				= ETH;
  heth.Init.AutoNegotiation 	= ETH_AUTONEGOTIATION_ENABLE;
  heth.Init.Speed 				= ETH_SPEED_100M;
  heth.Init.DuplexMode 			= ETH_MODE_FULLDUPLEX;
  heth.Init.PhyAddress 			= LAN8742A_PHY_ADDRESS;
  MACAddr[0] 					= 0x00;
  MACAddr[1] 					= 0x80;
  MACAddr[2] 					= 0xE1;
  MACAddr[3] 					= 0x00;
  MACAddr[4]					= 0x00;
  MACAddr[5] 					= 0x00;
  heth.Init.MACAddr 			= &MACAddr[0];
  heth.Init.RxMode 				= ETH_RXPOLLING_MODE;
  heth.Init.ChecksumMode 		= ETH_CHECKSUM_BY_HARDWARE;
  heth.Init.MediaInterface 		= ETH_MEDIA_INTERFACE_RMII;

  if (HAL_ETH_Init(&heth) != HAL_OK)
  {
    Error_Handler();
  }

}

static void MX_TIM14_Init(void)
{

  htim14.Instance 				= TIM14;
  htim14.Init.Prescaler 		= 7200 -1 ;
  htim14.Init.CounterMode 		= TIM_COUNTERMODE_UP;
  htim14.Init.Period 			= 10000;
  htim14.Init.ClockDivision 	= TIM_CLOCKDIVISION_DIV1;
  htim14.Init.AutoReloadPreload = TIM_AUTORELOAD_PRELOAD_DISABLE;
  if (HAL_TIM_Base_Init(&htim14) != HAL_OK)
  {
    Error_Handler();
  }

}

static void MX_USART3_UART_Init(void)
{

  huart3.Instance 					= USART3;
  huart3.Init.BaudRate 				= 115200;
  huart3.Init.WordLength			= UART_WORDLENGTH_8B;
  huart3.Init.StopBits 				= UART_STOPBITS_1;
  huart3.Init.Parity 				= UART_PARITY_NONE;
  huart3.Init.Mode 					= UART_MODE_TX_RX;
  huart3.Init.HwFlowCtl 			= UART_HWCONTROL_NONE;
  huart3.Init.OverSampling 			= UART_OVERSAMPLING_16;
  huart3.Init.OneBitSampling 		= UART_ONE_BIT_SAMPLE_DISABLE;
  huart3.AdvancedInit.AdvFeatureInit = UART_ADVFEATURE_NO_INIT;
  if (HAL_UART_Init(&huart3) != HAL_OK)
  {
    Error_Handler();
  }

}

static void MX_USB_OTG_FS_PCD_Init(void)
{

  hpcd_USB_OTG_FS.Instance 					= USB_OTG_FS;
  hpcd_USB_OTG_FS.Init.dev_endpoints 		= 6;
  hpcd_USB_OTG_FS.Init.speed 				= PCD_SPEED_FULL;
  hpcd_USB_OTG_FS.Init.dma_enable 			= DISABLE;
  hpcd_USB_OTG_FS.Init.phy_itface 			= PCD_PHY_EMBEDDED;
  hpcd_USB_OTG_FS.Init.Sof_enable 			= ENABLE;
  hpcd_USB_OTG_FS.Init.low_power_enable 	= DISABLE;
  hpcd_USB_OTG_FS.Init.lpm_enable 			= DISABLE;
  hpcd_USB_OTG_FS.Init.vbus_sensing_enable 	= ENABLE;
  hpcd_USB_OTG_FS.Init.use_dedicated_ep1 	= DISABLE;
  if (HAL_PCD_Init(&hpcd_USB_OTG_FS) != HAL_OK)
  {
    Error_Handler();
  }

}

static void MX_GPIO_Init(void)
{
	  GPIO_InitTypeDef GPIO_InitStruct = {0};

	  /* GPIO Ports Clock Enable */
	  __HAL_RCC_GPIOC_CLK_ENABLE();
	  __HAL_RCC_GPIOF_CLK_ENABLE();
	  __HAL_RCC_GPIOH_CLK_ENABLE();
	  __HAL_RCC_GPIOA_CLK_ENABLE();
	  __HAL_RCC_GPIOB_CLK_ENABLE();
	  __HAL_RCC_GPIOG_CLK_ENABLE();
	  __HAL_RCC_GPIOE_CLK_ENABLE();
	  __HAL_RCC_GPIOD_CLK_ENABLE();

	/* USER CODE BEGIN PIPO1 */
		HAL_GPIO_WritePin(GPIOF, GPIO_PIN_13, 	GPIO_PIN_RESET);
		HAL_GPIO_WritePin(GPIOE, GPIO_PIN_9, 	GPIO_PIN_RESET);
		HAL_GPIO_WritePin(GPIOE, GPIO_PIN_11, 	GPIO_PIN_RESET);
		HAL_GPIO_WritePin(GPIOF, GPIO_PIN_14, 	GPIO_PIN_RESET);
		HAL_GPIO_WritePin(GPIOE, GPIO_PIN_13, 	GPIO_PIN_RESET);
		HAL_GPIO_WritePin(GPIOF, GPIO_PIN_15, 	GPIO_PIN_RESET);
		HAL_GPIO_WritePin(GPIOG, GPIO_PIN_14, 	GPIO_PIN_RESET);
		HAL_GPIO_WritePin(GPIOG, GPIO_PIN_9, 	GPIO_PIN_RESET);
		HAL_GPIO_WritePin(GPIOE, GPIO_PIN_8, 	GPIO_PIN_RESET);
		HAL_GPIO_WritePin(GPIOE, GPIO_PIN_7, 	GPIO_PIN_RESET);
		HAL_GPIO_WritePin(GPIOF, CH2_TRIGGER, 	GPIO_PIN_RESET);
		HAL_GPIO_WritePin(GPIOF, NTC_BANK, 		GPIO_PIN_RESET);
	/* USER CODE END PIPO1 */

	  /*Configure GPIO pin Output Level */
	  HAL_GPIO_WritePin(GPIOF, GPIO_PIN_0|GPIO0_Pin|GPIO3_Pin|GPIO5_Pin, GPIO_PIN_RESET);

	  /*Configure GPIO pin Output Level */
	  HAL_GPIO_WritePin(GPIOB, LD1_Pin|LD3_Pin|LD2_Pin, GPIO_PIN_RESET);

	  /*Configure GPIO pin Output Level */
	  HAL_GPIO_WritePin(GPIOE, GPIO9_Pin|GPIO8_Pin|GPIO1_Pin|GPIO2_Pin
	                          |GPIO4_Pin, GPIO_PIN_RESET);

	  /*Configure GPIO pin Output Level */
	  HAL_GPIO_WritePin(GPIOG, USB_PowerSwitchOn_Pin|GPIO7_Pin|GPIO6_Pin, GPIO_PIN_RESET);

	  /*Configure GPIO pin Output Level */
	  HAL_GPIO_WritePin(GPIOD, GPIO_PIN_1, GPIO_PIN_RESET);

	  /*Configure GPIO pin : USER_Btn_Pin */
	  GPIO_InitStruct.Pin = USER_Btn_Pin;
	  GPIO_InitStruct.Mode = GPIO_MODE_IT_RISING;
	  GPIO_InitStruct.Pull = GPIO_NOPULL;
	  HAL_GPIO_Init(USER_Btn_GPIO_Port, &GPIO_InitStruct);

	  /*Configure GPIO pins : PG0 PG1 USB_OverCurrent_Pin */
	  //GPIO_InitStruct.Pin = GPIO_PIN_0|GPIO_PIN_1|USB_OverCurrent_Pin;
	  GPIO_InitStruct.Pin = GPIO_PIN_0;
	  GPIO_InitStruct.Mode = GPIO_MODE_INPUT;
	  GPIO_InitStruct.Pull = GPIO_PULLDOWN;
	  HAL_GPIO_Init(GPIOG, &GPIO_InitStruct);

	  /*Configure GPIO pin : CH1_Input_interrupt_Pin */
	  GPIO_InitStruct.Pin 	= GPIO_PIN_1;
	  GPIO_InitStruct.Mode 	= GPIO_MODE_IT_RISING_FALLING;
	  GPIO_InitStruct.Pull 	= GPIO_NOPULL;
	  HAL_GPIO_Init(GPIOG, &GPIO_InitStruct);

	  /*Configure GPIO pins : PF2 - start from PLC */
	  GPIO_InitStruct.Pin = GPIO_PIN_2 | GPIO_PIN_1;
	  GPIO_InitStruct.Mode = GPIO_MODE_INPUT;
	  GPIO_InitStruct.Pull = GPIO_PULLDOWN;
	  HAL_GPIO_Init(GPIOF, &GPIO_InitStruct);

	  /*Configure GPIO pin : PD0 */
	  GPIO_InitStruct.Pin = GPIO_PIN_0;
	  GPIO_InitStruct.Mode = GPIO_MODE_OUTPUT_PP;
	  GPIO_InitStruct.Pull = GPIO_NOPULL;
	  GPIO_InitStruct.Speed = GPIO_SPEED_FREQ_VERY_HIGH;
	  HAL_GPIO_Init(GPIOD, &GPIO_InitStruct);

	  /*Configure GPIO pins : PE */
	  GPIO_InitStruct.Pin = GPIO_PIN_3 | GPIO_PIN_6;
	  GPIO_InitStruct.Mode = GPIO_MODE_INPUT;
	  GPIO_InitStruct.Pull = GPIO_PULLDOWN;
	  HAL_GPIO_Init(GPIOE, &GPIO_InitStruct);

	  /*Configure GPIO pins : GPIO9_Pin GPIO8_Pin GPIO1_Pin GPIO2_Pin
	                           GPIO4_Pin */
	  GPIO_InitStruct.Pin = GPIO_PIN_7 | GPIO_PIN_8 | GPIO_PIN_9 | GPIO_PIN_11 | GPIO_PIN_13;
	  GPIO_InitStruct.Mode = GPIO_MODE_OUTPUT_PP;
	  GPIO_InitStruct.Pull = GPIO_NOPULL;
	  GPIO_InitStruct.Speed = GPIO_SPEED_FREQ_VERY_HIGH;
	  HAL_GPIO_Init(GPIOE, &GPIO_InitStruct);

	  /*Configure GPIO pins : PF0 GPIO0_Pin GPIO3_Pin GPIO5_Pin */
	  GPIO_InitStruct.Pin = GPIO_PIN_0 | GPIO_PIN_7 | GPIO_PIN_8 | GPIO_PIN_9| GPIO_PIN_13 | GPIO_PIN_14 | GPIO_PIN_15 ;
	  GPIO_InitStruct.Mode = GPIO_MODE_OUTPUT_PP;
	  GPIO_InitStruct.Pull = GPIO_NOPULL;
	  GPIO_InitStruct.Speed = GPIO_SPEED_FREQ_VERY_HIGH;
	  HAL_GPIO_Init(GPIOF, &GPIO_InitStruct);

	  /*Configure GPIO pins : USB_PowerSwitchOn_Pin GPIO7_Pin GPIO6_Pin */
	  GPIO_InitStruct.Pin = GPIO_PIN_9| GPIO_PIN_14;
	  GPIO_InitStruct.Mode = GPIO_MODE_OUTPUT_PP;
	  GPIO_InitStruct.Pull = GPIO_NOPULL;
	  GPIO_InitStruct.Speed = GPIO_SPEED_FREQ_VERY_HIGH;
	  HAL_GPIO_Init(GPIOG, &GPIO_InitStruct);

	  /*Configure GPIO pins : LD1_Pin LD3_Pin LD2_Pin */
	  GPIO_InitStruct.Pin = LD1_Pin|LD3_Pin|LD2_Pin;
	  GPIO_InitStruct.Mode = GPIO_MODE_OUTPUT_PP;
	  GPIO_InitStruct.Pull = GPIO_NOPULL;
	  GPIO_InitStruct.Speed = GPIO_SPEED_FREQ_LOW;
	  HAL_GPIO_Init(GPIOB, &GPIO_InitStruct);

	  /*Configure GPIO pin : PD1 */
	  GPIO_InitStruct.Pin = GPIO_PIN_1 | GPIO_PIN_0;
	  GPIO_InitStruct.Mode = GPIO_MODE_OUTPUT_PP;
	  GPIO_InitStruct.Pull = GPIO_NOPULL;
	  GPIO_InitStruct.Speed = GPIO_SPEED_FREQ_VERY_HIGH;
	  HAL_GPIO_Init(GPIOD, &GPIO_InitStruct);

	  /* EXTI interrupt init*/
	  HAL_NVIC_SetPriority(EXTI1_IRQn, 0, 0);
	  HAL_NVIC_EnableIRQ(EXTI1_IRQn);

}

#if 0
static void MX_GPIO_Init(void)
{
  GPIO_InitTypeDef GPIO_InitStruct = {0};

  /* GPIO Ports Clock Enable */
  __HAL_RCC_GPIOC_CLK_ENABLE();
  __HAL_RCC_GPIOF_CLK_ENABLE();
  __HAL_RCC_GPIOH_CLK_ENABLE();
  __HAL_RCC_GPIOA_CLK_ENABLE();
  __HAL_RCC_GPIOB_CLK_ENABLE();
  __HAL_RCC_GPIOG_CLK_ENABLE();
  __HAL_RCC_GPIOE_CLK_ENABLE();
  __HAL_RCC_GPIOD_CLK_ENABLE();

  /*Configure GPIO pin Output Level */
  HAL_GPIO_WritePin(GPIOF, GPIO_PIN_0|GPIO0_Pin|GPIO3_Pin|GPIO5_Pin, GPIO_PIN_RESET);

  /*Configure GPIO pin Output Level */
  HAL_GPIO_WritePin(GPIOB, LD1_Pin|LD3_Pin|LD2_Pin, GPIO_PIN_RESET);

  /*Configure GPIO pin Output Level */
  HAL_GPIO_WritePin(GPIOE, GPIO9_Pin|GPIO8_Pin|GPIO1_Pin|GPIO2_Pin
                          |GPIO4_Pin, GPIO_PIN_RESET);

  /*Configure GPIO pin Output Level */
  HAL_GPIO_WritePin(GPIOG, USB_PowerSwitchOn_Pin|GPIO7_Pin|GPIO6_Pin, GPIO_PIN_RESET);

  /*Configure GPIO pin Output Level */
  HAL_GPIO_WritePin(GPIOD, GPIO_PIN_1, GPIO_PIN_RESET);

  /*Configure GPIO pin : USER_Btn_Pin */
  GPIO_InitStruct.Pin 	= USER_Btn_Pin;
  GPIO_InitStruct.Mode	= GPIO_MODE_IT_RISING;
  GPIO_InitStruct.Pull 	= GPIO_NOPULL;
  HAL_GPIO_Init(USER_Btn_GPIO_Port, &GPIO_InitStruct);

  /*Configure GPIO pins : PF0 GPIO0_Pin GPIO3_Pin GPIO5_Pin */
  GPIO_InitStruct.Pin 	= GPIO_PIN_0|GPIO0_Pin|GPIO3_Pin|GPIO5_Pin;
  GPIO_InitStruct.Mode 	= GPIO_MODE_OUTPUT_PP;
  GPIO_InitStruct.Pull 	= GPIO_NOPULL;
  GPIO_InitStruct.Speed = GPIO_SPEED_FREQ_LOW;
  HAL_GPIO_Init(GPIOF, &GPIO_InitStruct);

  /*Configure GPIO pins : LD1_Pin LD3_Pin LD2_Pin */
  GPIO_InitStruct.Pin 	= LD1_Pin|LD3_Pin|LD2_Pin;
  GPIO_InitStruct.Mode 	= GPIO_MODE_OUTPUT_PP;
  GPIO_InitStruct.Pull 	= GPIO_NOPULL;
  GPIO_InitStruct.Speed = GPIO_SPEED_FREQ_LOW;
  HAL_GPIO_Init(GPIOB, &GPIO_InitStruct);

  /*Configure GPIO pins : CH2_Input_Pin USB_OverCurrent_Pin */
  GPIO_InitStruct.Pin 	= CH2_Input_Pin|USB_OverCurrent_Pin;
  GPIO_InitStruct.Mode 	= GPIO_MODE_INPUT;
  GPIO_InitStruct.Pull 	= GPIO_NOPULL;
  HAL_GPIO_Init(GPIOG, &GPIO_InitStruct);

  /*Configure GPIO pin : CH1_Input_interrupt_Pin */
  GPIO_InitStruct.Pin 	= CH1_Input_interrupt_Pin;
  GPIO_InitStruct.Mode 	= GPIO_MODE_IT_RISING_FALLING;
  GPIO_InitStruct.Pull 	= GPIO_NOPULL;
  HAL_GPIO_Init(CH1_Input_interrupt_GPIO_Port, &GPIO_InitStruct);

  /*Configure GPIO pins : GPIO9_Pin GPIO8_Pin GPIO1_Pin GPIO2_Pin
                           GPIO4_Pin */
  GPIO_InitStruct.Pin 	= GPIO9_Pin|GPIO8_Pin|GPIO1_Pin|GPIO2_Pin
                          |GPIO4_Pin;
  GPIO_InitStruct.Mode 	= GPIO_MODE_OUTPUT_PP;
  GPIO_InitStruct.Pull 	= GPIO_NOPULL;
  GPIO_InitStruct.Speed = GPIO_SPEED_FREQ_LOW;
  HAL_GPIO_Init(GPIOE, &GPIO_InitStruct);

  /*Configure GPIO pins : USB_PowerSwitchOn_Pin GPIO7_Pin GPIO6_Pin */
  GPIO_InitStruct.Pin 	= USB_PowerSwitchOn_Pin|GPIO7_Pin|GPIO6_Pin;
  GPIO_InitStruct.Mode 	= GPIO_MODE_OUTPUT_PP;
  GPIO_InitStruct.Pull 	= GPIO_NOPULL;
  GPIO_InitStruct.Speed = GPIO_SPEED_FREQ_LOW;
  HAL_GPIO_Init(GPIOG, &GPIO_InitStruct);

  /*Configure GPIO pin : PD0 */
  GPIO_InitStruct.Pin 	= GPIO_PIN_0;
  GPIO_InitStruct.Mode 	= GPIO_MODE_INPUT;
  GPIO_InitStruct.Pull 	= GPIO_NOPULL;
  HAL_GPIO_Init(GPIOD, &GPIO_InitStruct);

  /*Configure GPIO pin : PD1 */
  GPIO_InitStruct.Pin 	= GPIO_PIN_1;
  GPIO_InitStruct.Mode 	= GPIO_MODE_OUTPUT_PP;
  GPIO_InitStruct.Pull 	= GPIO_NOPULL;
  GPIO_InitStruct.Speed = GPIO_SPEED_FREQ_LOW;
  HAL_GPIO_Init(GPIOD, &GPIO_InitStruct);

  /* EXTI interrupt init*/
  HAL_NVIC_SetPriority(EXTI1_IRQn, 0, 0);
  HAL_NVIC_EnableIRQ(EXTI1_IRQn);

}
#endif
/* USER CODE BEGIN 4 */
void ToggleNTCBank()
{
	//toggle NTC banks for Dewesoft measurement
	if (IdleCounter >= 72000){
		IdleCounter = 12001;
	}
	else if (IdleCounter >= 42000){
		HAL_GPIO_WritePin(GPIOF, NTC_BANK, GPIO_PIN_SET);	//reset temperature bank select pin
	}
	else if (IdleCounter >= 12000){
		HAL_GPIO_WritePin(GPIOF, NTC_BANK, GPIO_PIN_RESET);	//reset temperature bank select pin
		if (IdleCounter == 12000)  {
			sprintf(msg, "Counter1: %d, Counter2: %d \r\n", Counter1, Counter2);
			HAL_UART_Transmit(&huart3, (uint8_t*)msg, strlen(msg), HAL_MAX_DELAY);
		}
	}
	return;
}

int CheckIdleCurrent() {
int tResult = 0;
	//check if current dropped under defined values
	//after IGBTs are switched off
	if (ReadADC_cont() > ADC_noCurrent_val) {
		FalseLowCurrentCounter++;
	}
	else {
		FalseLowCurrentCounter--;
	}
	if (FalseLowCurrentCounter > 20) {
		FalseLowCurrentCounter = 20;
		tResult = -1;
	}
	else if (FalseLowCurrentCounter < 0) {
		FalseLowCurrentCounter = 0;
		tResult = 1;
	}
	return tResult;
}

void IdleCurrentMeasurementTest() {
	if (curValsCntr == 2000) {
		currValsMax = currVals[0];
		currValsMin = currVals[0];
		for (i = 0; i < 1999; i++) {
			sprintf(msg, "%d\r\n ",currVals[i]);
			HAL_UART_Transmit(&huart3, (uint8_t*)msg, strlen(msg), HAL_MAX_DELAY);
			if (currVals[i] > currValsMax) currValsMax = currVals[i];
			if (currVals[i] < currValsMin) currValsMin = currVals[i];
			currVals[i] = 0;
		}
		sprintf(msg, "currValsMax = %d ; currValsMin= %d \r\n", currValsMax, currValsMin);
		HAL_UART_Transmit(&huart3, (uint8_t*)msg, strlen(msg), HAL_MAX_DELAY);
		curValsCntr++;
	}
	return;
}

void DWT_Init(void)
{
    CoreDebug->DEMCR |= CoreDebug_DEMCR_TRCENA_Msk;  // enable trace
    DWT->LAR = 0xC5ACCE55;                            // unlock (F7!)
    DWT->CYCCNT = 0;
    DWT->CTRL |= DWT_CTRL_CYCCNTENA_Msk;              // enable counter
}

/* USER CODE END 4 */

void Error_Handler(void)
{
  __disable_irq();
  while (1)
  {
  }
}
